VERSION 5.8 ;
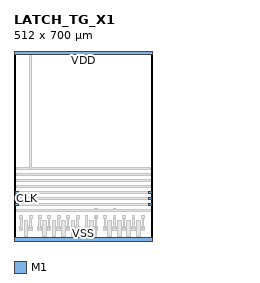
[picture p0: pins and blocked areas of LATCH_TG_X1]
MACRO LATCH_TG_X1
  CLASS CORE ;
  ORIGIN 0 0 ;
  SIZE 512 BY 700 ;
  SITE ICPS2023_5_ROW700 ;
  PIN D
    DIRECTION INPUT ;
    USE SIGNAL ;
    PORT
      LAYER M1 ;
        RECT 5 130 15 140 ;
        RECT 497 130 507 140 ;
    END
  END D
  PIN CLK
    DIRECTION INPUT ;
    USE SIGNAL ;
    PORT
      LAYER M1 ;
        RECT 5 152 15 162 ;
        RECT 497 152 507 162 ;
    END
  END CLK
  PIN Q
    DIRECTION OUTPUT ;
    USE SIGNAL ;
    PORT
      LAYER M1 ;
        RECT 5 174 15 184 ;
        RECT 497 174 507 184 ;
    END
  END Q
  PIN VDD
    DIRECTION INOUT ;
    USE POWER ;
    PORT
      LAYER M1 ;
        RECT 0 688 512 700 ;
    END
  END VDD
  PIN VSS
    DIRECTION INOUT ;
    USE GROUND ;
    PORT
      LAYER M1 ;
        RECT 0 0 512 12 ;
    END
  END VSS
  OBS
    LAYER M1 ;
      RECT 20 39.5 33 52.5 ;
      RECT 55 39.5 68 52.5 ;
      RECT 37.5 16 50.5 29 ;
      RECT 37.5 63 50.5 76 ;
      RECT 37 16 51 76 ;
      RECT 23.5 46 29.5 89 ;
      RECT 21.5 84 31.5 94 ;
      RECT 21.5 218 31.5 228 ;
      RECT 58.5 46 64.5 89 ;
      RECT 56.5 84 66.5 94 ;
      RECT 56.5 262 66.5 272 ;
      RECT 39 196 49 206 ;
      RECT 88 39.5 101 52.5 ;
      RECT 123 39.5 136 52.5 ;
      RECT 158 39.5 171 52.5 ;
      RECT 193 39.5 206 52.5 ;
      RECT 228 39.5 241 52.5 ;
      RECT 105.5 16 118.5 29 ;
      RECT 105.5 63 118.5 76 ;
      RECT 105 16 119 76 ;
      RECT 140.5 16 153.5 29 ;
      RECT 140.5 63 153.5 76 ;
      RECT 140 16 154 76 ;
      RECT 175.5 16 188.5 29 ;
      RECT 175.5 63 188.5 76 ;
      RECT 175 16 189 76 ;
      RECT 210.5 16 223.5 29 ;
      RECT 210.5 63 223.5 76 ;
      RECT 210 16 224 76 ;
      RECT 91.5 46 97.5 89 ;
      RECT 89.5 84 99.5 94 ;
      RECT 89.5 240 99.5 250 ;
      RECT 126.5 46 132.5 89 ;
      RECT 124.5 84 134.5 94 ;
      RECT 124.5 262 134.5 272 ;
      RECT 161.5 46 167.5 89 ;
      RECT 159.5 84 169.5 94 ;
      RECT 159.5 174 169.5 184 ;
      RECT 196.5 46 202.5 89 ;
      RECT 194.5 84 204.5 94 ;
      RECT 194.5 196 204.5 206 ;
      RECT 231.5 46 237.5 89 ;
      RECT 229.5 84 239.5 94 ;
      RECT 229.5 130 239.5 140 ;
      RECT 107 152 117 162 ;
      RECT 142 218 152 228 ;
      RECT 177 152 187 162 ;
      RECT 212 240 222 250 ;
      RECT 261 39.5 274 52.5 ;
      RECT 296 39.5 309 52.5 ;
      RECT 278.5 16 291.5 29 ;
      RECT 278.5 63 291.5 76 ;
      RECT 278 16 292 76 ;
      RECT 264.5 46 270.5 89 ;
      RECT 262.5 84 272.5 94 ;
      RECT 262.5 218 272.5 228 ;
      RECT 299.5 46 305.5 89 ;
      RECT 297.5 84 307.5 94 ;
      RECT 297.5 108 307.5 118 ;
      RECT 280 196 290 206 ;
      RECT 329 39.5 342 52.5 ;
      RECT 364 39.5 377 52.5 ;
      RECT 399 39.5 412 52.5 ;
      RECT 434 39.5 447 52.5 ;
      RECT 469 39.5 482 52.5 ;
      RECT 346.5 16 359.5 29 ;
      RECT 346.5 63 359.5 76 ;
      RECT 346 16 360 76 ;
      RECT 381.5 16 394.5 29 ;
      RECT 381.5 63 394.5 76 ;
      RECT 381 16 395 76 ;
      RECT 416.5 16 429.5 29 ;
      RECT 416.5 63 429.5 76 ;
      RECT 416 16 430 76 ;
      RECT 451.5 16 464.5 29 ;
      RECT 451.5 63 464.5 76 ;
      RECT 451 16 465 76 ;
      RECT 332.5 46 338.5 89 ;
      RECT 330.5 84 340.5 94 ;
      RECT 330.5 240 340.5 250 ;
      RECT 367.5 46 373.5 89 ;
      RECT 365.5 84 375.5 94 ;
      RECT 365.5 108 375.5 118 ;
      RECT 402.5 46 408.5 89 ;
      RECT 400.5 84 410.5 94 ;
      RECT 400.5 174 410.5 184 ;
      RECT 437.5 46 443.5 89 ;
      RECT 435.5 84 445.5 94 ;
      RECT 435.5 196 445.5 206 ;
      RECT 472.5 46 478.5 89 ;
      RECT 470.5 84 480.5 94 ;
      RECT 470.5 130 480.5 140 ;
      RECT 348 152 358 162 ;
      RECT 383 218 393 228 ;
      RECT 418 240 428 250 ;
      RECT 453 152 463 162 ;
      RECT 10 110 502 116 ;
      RECT 10 132 502 138 ;
      RECT 10 154 502 160 ;
      RECT 10 176 502 182 ;
      RECT 10 198 502 204 ;
      RECT 10 220 502 226 ;
      RECT 10 242 502 248 ;
      RECT 10 264 502 270 ;
      RECT 299.5 3 305.5 92 ;
      RECT 58.5 264 64.5 697 ;
  END
END LATCH_TG_X1
